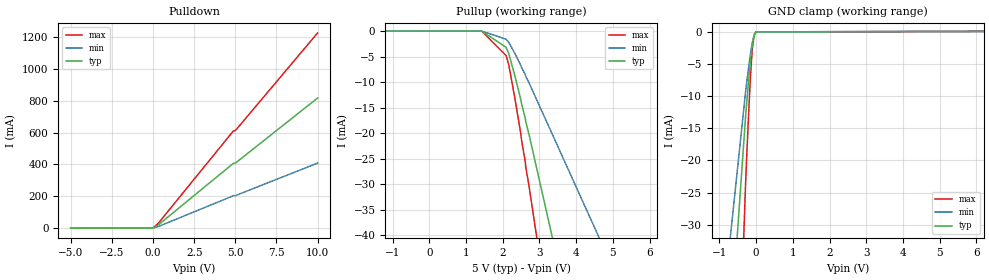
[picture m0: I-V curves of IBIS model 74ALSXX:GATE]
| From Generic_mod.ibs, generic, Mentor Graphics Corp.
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[Model]   74ALSXX:GATE
Model_type   I/O
Polarity   Non-Inverting
Vinl  =   0.800V
Vinh  =   2.000V
Vmeas =   1.500V
Cref  =  50.000pF
Rref  =   1.000kOhm
Vref  =   0.000V
|   typ   min   max
C_comp   5.000pF   2.500pF   7.500pF
[Voltage Range]   5.000V   4.500V   5.500V
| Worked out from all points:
|   slope of the pulldown table from 0 to 0.75 V, typ, clamps not added: 13.1 ohm
|   GND clamp passes 1 mA (typ) near -0.07 V on its own axis
[Pulldown]
| Voltage   I(typ)   I(min)   I(max)
-5V       0A         0A         0A
0V        0A         0A         0A
352mV     23.07mA    11.53mA    34.6mA
4.89V     407.6mA    203.8mA    611.4mA
5V        408.1mA    204.1mA    612.2mA
10V       817.4mA    408.7mA    1.226A
[Pullup]
| Voltage   I(typ)   I(min)   I(max)
-3.571V   0A         0A         0A
1.429V    0A         0A         0A
2.096V    -3.2mA     -1.6mA     -4.8mA
2.17V     -4.5mA     -2.25mA    -6.75mA
2.337V    -8.9mA     -4.45mA    -13.35mA
2.489V    -13.3mA    -6.65mA    -19.95mA
2.519V    -14.4mA    -7.2mA     -21.6mA
2.619V    -17.2mA    -8.6mA     -25.8mA
2.629V    -17.8mA    -8.9mA     -26.7mA
2.709V    -20mA      -10mA      -30mA
6.389V    -137.1mA   -68.55mA   -205.6mA
11.39V    -275mA     -137.5mA   -412.5mA
[GND Clamp]
| Voltage   I(typ)   I(min)   I(max)
-5V       -398mA     -266mA     -792.9mA
-287.6mV  -13.2mA    -9.331mA   -23.71mA
-255.6mV  -10.96mA   -7.82mA    -19.31mA
-189.7mV  -6.623mA   -4.878mA   -10.95mA
-157.7mV  -4.718mA   -3.565mA   -7.397mA
-126.8mV  -3.095mA   -2.424mA   -4.507mA
-106.8mV  -2.189mA   -1.769mA   -2.995mA
-95.35mV  -1.737mA   -1.433mA   -2.284mA
-66.38mV  -840.9uA   -736.6uA   -995.6uA
-39.12mV  -326uA     -301.8uA   -356uA
0V        0A         0A         0A
10V       128uA      128uA      128uA
[Ramp]
|   typ   min   max
dV/dt_r   1.075V/3.180ns   0.643V/5.724ns   1.445V/2.332ns
dV/dt_f   2.388V/2.400ns   1.801V/4.320ns   2.810V/1.760ns
R_load =  50.000Ohm
|------------------- End of 74ALSXX:GATE --------------------------------------
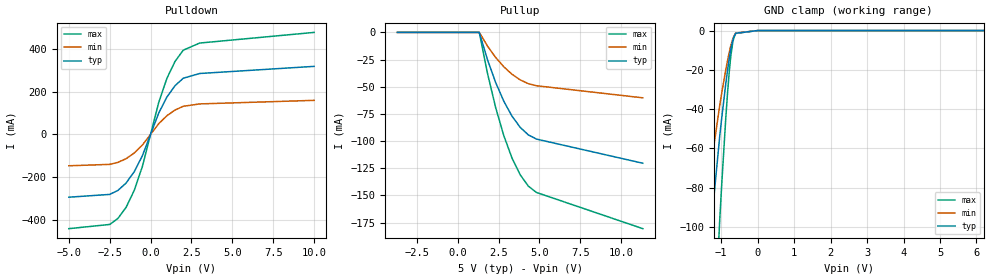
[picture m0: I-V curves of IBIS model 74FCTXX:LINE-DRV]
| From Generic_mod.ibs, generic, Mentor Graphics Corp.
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[Model]   74FCTXX:LINE-DRV
Model_type   I/O
Polarity   Non-Inverting
Vinl  =   0.800V
Vinh  =   2.000V
Vmeas =   1.500V
Cref  =  50.000pF
Rref  =   1.000kOhm
Vref  =   0.000V
|   typ   min   max
C_comp   12.000pF   6.000pF   18.000pF
[Voltage Range]   5.000V   4.500V   5.500V
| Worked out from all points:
|   slope of the pulldown table from 0 to 0.75 V, typ, clamps not added: 5.46 ohm
[Pulldown]
| Voltage   I(typ)   I(min)   I(max)
-5V       -294.3mA   -147.2mA   -441.5mA
-2.5V     -281.2mA   -140.6mA   -421.8mA
-2V       -262.7mA   -131.3mA   -394mA
-1.5V     -228.2mA   -114.1mA   -342.2mA
-1V       -174.9mA   -87.45mA   -262.4mA
-500mV    -100mA     -50mA      -150mA
500mV     100mA      50mA       150mA
1V        174.9mA    87.45mA    262.4mA
1.5V      228.2mA    114.1mA    342.2mA
2V        262.7mA    131.3mA    394mA
3V        284.8mA    142.4mA    427.3mA
10V       318.2mA    159.1mA    477.2mA
[Pullup]
| Voltage   I(typ)   I(min)   I(max)
-3.676V   0A         0A         0A
1.324V    0A         0A         0A
1.824V    -25mA      -12.5mA    -37.5mA
2.324V    -46.05mA   -23.03mA   -69.08mA
2.824V    -63.35mA   -31.67mA   -95.02mA
3.324V    -77.06mA   -38.53mA   -115.6mA
3.824V    -87.34mA   -43.67mA   -131mA
4.324V    -94.33mA   -47.17mA   -141.5mA
4.824V    -98.19mA   -49.09mA   -147.3mA
11.32V    -120.4mA   -60.21mA   -180.6mA
[GND Clamp]
| Voltage   I(typ)   I(min)   I(max)
-5V       -820mA     -549.2mA   -1.627A
-1.036V   -53.26mA   -37.7mA    -95.41mA
-984.1mV  -44.54mA   -31.82mA   -78.32mA
-874.8mV  -27.32mA   -20.14mA   -45.09mA
-822.5mV  -19.88mA   -15.03mA   -31.19mA
-775.2mV  -13.87mA   -10.82mA   -20.4mA
-735.6mV  -9.524mA   -7.699mA   -13.05mA
-678.8mV  -4.762mA   -4.11mA    -5.792mA
-653.9mV  -3.293mA   -2.932mA   -3.809mA
-601.6mV  -1.347mA   -1.27mA    -1.438mA
0V        0A         0A         0A
10V       0A         0A         0A
[Ramp]
|   typ   min   max
dV/dt_r   1.524V/1.500ns   0.973V/2.700ns   1.946V/1.100ns
dV/dt_f   2.727V/1.500ns   2.210V/2.700ns   3.094V/1.100ns
R_load =  50.000Ohm
|------------------- End of 74FCTXX:LINE-DRV ----------------------------------
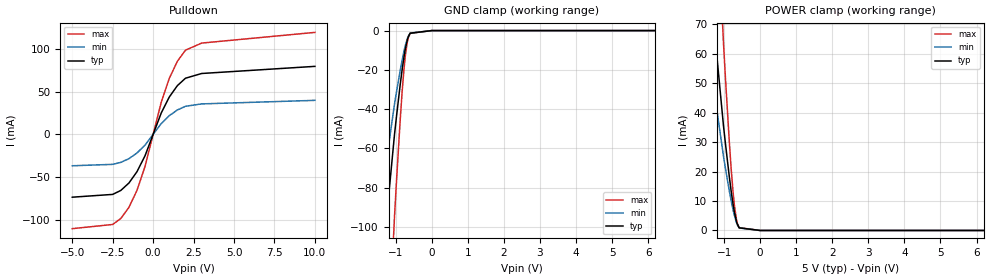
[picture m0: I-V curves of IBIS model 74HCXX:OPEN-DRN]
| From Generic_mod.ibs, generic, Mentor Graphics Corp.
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[Model]   74HCXX:OPEN-DRN
Model_type   I/O_open_drain
Polarity   Non-Inverting
Vinl  =   3.000V
Vinh  =   4.000V
Vmeas =   3.500V
Cref  =  50.000pF
Rref  =   50.00Ohm
Vref  =   5.000V
|   typ   min   max
C_comp   5.000pF   2.500pF   7.500pF
[Voltage Range]   5.000V   4.500V   5.500V
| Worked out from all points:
|   slope of the pulldown table from 0 to 0.75 V, typ, clamps not added: 21.8 ohm
|   POWER clamp passes 1 mA (typ) near -0.59 V on its own axis
[Pulldown]
| Voltage   I(typ)   I(min)   I(max)
-5V       -73.58mA   -36.79mA   -110.4mA
-2.5V     -70.3mA    -35.15mA   -105.5mA
-2V       -65.67mA   -32.83mA   -98.5mA
-1.5V     -57.04mA   -28.52mA   -85.56mA
-1V       -43.73mA   -21.86mA   -65.59mA
-500mV    -25mA      -12.5mA    -37.5mA
500mV     25mA       12.5mA     37.5mA
1V        43.73mA    21.86mA    65.59mA
1.5V      57.04mA    28.52mA    85.56mA
2V        65.67mA    32.83mA    98.5mA
3V        71.21mA    35.61mA    106.8mA
10V       79.54mA    39.77mA    119.3mA
|[Pullup]
| Voltage   I(typ)   I(min)   I(max)
|   0.0000V   0.0000A   0.0000A   0.0000A
|  500.0000mV   0.0000A   0.0000A   0.0000A
| 1000.0000mV   0.0000A   0.0000A   0.0000A
|   1.5000V   0.0000A   0.0000A   0.0000A
|   2.0000V   0.0000A   0.0000A   0.0000A
|   2.5000V   0.0000A   0.0000A   0.0000A
|   3.0000V   0.0000A   0.0000A   0.0000A
|   3.5000V   0.0000A   0.0000A   0.0000A
|   4.0000V   0.0000A   0.0000A   0.0000A
|   4.5000V   0.0000A   0.0000A   0.0000A
|   5.0000V   0.0000A   0.0000A   0.0000A
|   5.5000V   -500.5005nA   -250.2503nA   -750.7508nA
|   6.0000V   -922.0229nA   -461.0115nA   -1.3830uA
|   6.5000V   -1.2682uA   -634.1204nA   -1.9024uA
|   7.0000V   -1.5428uA   -771.4136nA   -2.3142uA
|   7.5000V   -1.7485uA   -874.2687nA   -2.6228uA
|   8.0000V   -1.8886uA   -944.2929nA   -2.8329uA
|   8.5000V   -1.9657uA   -982.8636nA   -2.9486uA
|   9.0000V   -2.0011uA   -1.0005uA   -3.0016uA
|   9.5000V   -2.0351uA   -1.0175uA   -3.0526uA
|   10.0000V   -2.0690uA   -1.0345uA   -3.1036uA
|   15.0000V   -2.4107uA   -1.2053uA   -3.6160uA
[GND Clamp]
| Voltage   I(typ)   I(min)   I(max)
-5V       -820mA     -549.2mA   -1.627A
-1.036V   -53.26mA   -37.7mA    -95.41mA
-984.1mV  -44.54mA   -31.82mA   -78.32mA
-874.8mV  -27.32mA   -20.14mA   -45.09mA
-822.5mV  -19.88mA   -15.03mA   -31.19mA
-775.2mV  -13.87mA   -10.82mA   -20.4mA
-735.6mV  -9.524mA   -7.699mA   -13.05mA
-678.8mV  -4.762mA   -4.11mA    -5.792mA
-653.9mV  -3.293mA   -2.932mA   -3.809mA
-601.6mV  -1.347mA   -1.27mA    -1.438mA
0V        0A         0A         0A
10V       0A         0A         0A
[POWER Clamp]
| Voltage   I(typ)   I(min)   I(max)
-5V       549.2mA    367.8mA    1.09A
-1.017V   35.51mA    25.14mA    63.62mA
-964.9mV  29.7mA     21.22mA    52.23mA
-855.5mV  18.21mA    13.43mA    30.06mA
-803.2mV  13.26mA    10.02mA    20.8mA
-755.9mV  9.247mA    7.215mA    13.6mA
-716.3mV  6.349mA    5.133mA    8.699mA
-659.5mV  3.175mA    2.74mA     3.862mA
-634.6mV  2.195mA    1.955mA    2.54mA
-582.3mV  897.7uA    846.6uA    958.8uA
0V        0A         0A         0A
10V       0A         0A         0A
[Ramp]
|   typ   min   max
dV/dt_r   1.891V/1.800ns   1.061V/3.240ns   2.456V/1.320ns
dV/dt_f   1.891V/1.800ns   1.061V/3.240ns   2.456V/1.320ns
R_load =  50.000Ohm
|------------------- End of 74HCXX:OPEN-DRN -----------------------------------
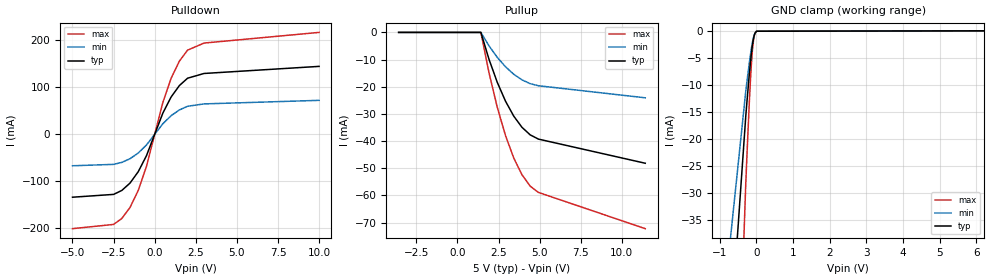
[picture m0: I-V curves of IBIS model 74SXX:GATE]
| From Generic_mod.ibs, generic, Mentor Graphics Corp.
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[Model]   74SXX:GATE
Model_type   I/O
Polarity   Non-Inverting
Vinl  =   0.800V
Vinh  =   2.000V
Vmeas =   1.500V
Cref  =  50.000pF
Rref  =   1.000kOhm
Vref  =   0.000V
|   typ   min   max
C_comp   8.000pF   4.000pF   12.000pF
[Voltage Range]   5.000V   4.500V   5.500V
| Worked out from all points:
|   slope of the pulldown table from 0 to 0.75 V, typ, clamps not added: 12 ohm
|   GND clamp passes 1 mA (typ) near -0.07 V on its own axis
[Pulldown]
| Voltage   I(typ)   I(min)   I(max)
-5V       -133.8mA   -66.89mA   -200.7mA
-2.5V     -127.8mA   -63.91mA   -191.7mA
-2V       -119.4mA   -59.7mA    -179.1mA
-1.5V     -103.7mA   -51.85mA   -155.6mA
-1V       -79.5mA    -39.75mA   -119.3mA
-500mV    -45.45mA   -22.73mA   -68.18mA
500mV     45.45mA    22.73mA    68.18mA
1V        79.5mA     39.75mA    119.3mA
1.5V      103.7mA    51.85mA    155.6mA
2V        119.4mA    59.7mA     179.1mA
3V        129.5mA    64.74mA    194.2mA
10V       144.6mA    72.31mA    216.9mA
[Pullup]
| Voltage   I(typ)   I(min)   I(max)
-3.577V   0A         0A         0A
1.423V    0A         0A         0A
1.923V    -10mA      -5mA       -15mA
2.423V    -18.42mA   -9.211mA   -27.63mA
2.923V    -25.34mA   -12.67mA   -38.01mA
3.423V    -30.83mA   -15.41mA   -46.24mA
3.923V    -34.94mA   -17.47mA   -52.4mA
4.423V    -37.73mA   -18.87mA   -56.6mA
4.923V    -39.28mA   -19.64mA   -58.91mA
11.42V    -48.17mA   -24.08mA   -72.25mA
[GND Clamp]
| Voltage   I(typ)   I(min)   I(max)
-5V       -477.1mA   -318.8mA   -950.4mA
-292.8mV  -15.86mA   -11.21mA   -28.48mA
-261mV    -13.19mA   -9.409mA   -23.24mA
-194.9mV  -7.964mA   -5.866mA   -13.17mA
-163.1mV  -5.696mA   -4.304mA   -8.933mA
-132mV    -3.732mA   -2.924mA   -5.434mA
-112.1mV  -2.653mA   -2.144mA   -3.63mA
-100.2mV  -2.09mA    -1.726mA   -2.744mA
-71.08mV  -1.017mA   -891.7uA   -1.201mA
-42.9mV   -392uA     -364uA     -426.5uA
0V        0A         0A         0A
10V       128uA      128uA      128uA
[Ramp]
|   typ   min   max
dV/dt_r   0.930V/1.500ns   0.493V/2.700ns   1.323V/1.100ns
dV/dt_f   2.392V/900.000ps   1.660V/1.620ns   2.840V/660.000ps
R_load =  50.000Ohm
|------------------- End of 74SXX:GATE ----------------------------------------
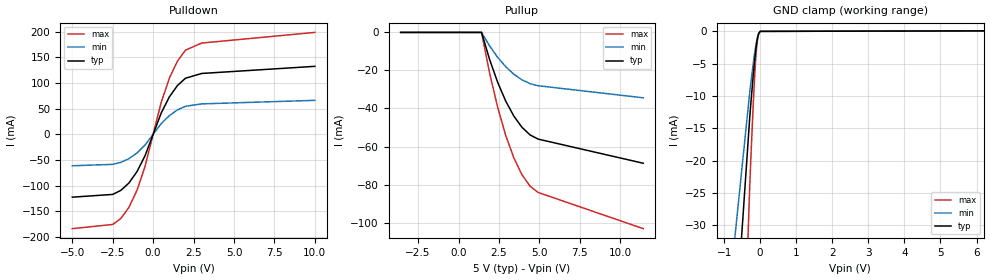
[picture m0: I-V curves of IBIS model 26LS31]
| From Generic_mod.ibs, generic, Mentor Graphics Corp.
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[Model]   26LS31
Model_type   I/O
Polarity   Non-Inverting
Vinl  =   0.800V
Vinh  =   2.000V
Vmeas =   1.500V
Cref  =  50.000pF
Rref  =   1.000kOhm
Vref  =   0.000V
|   typ   min   max
C_comp   5.000pF   2.500pF   7.500pF
[Voltage Range]   5.000V   4.500V   5.500V
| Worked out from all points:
|   slope of the pulldown table from 0 to 0.75 V, typ, clamps not added: 13.1 ohm
|   GND clamp passes 1 mA (typ) near -0.07 V on its own axis
[Pulldown]
| Voltage   I(typ)   I(min)   I(max)
-5V       -122.6mA   -61.32mA   -184mA
-2.5V     -117.2mA   -58.59mA   -175.8mA
-2V       -109.4mA   -54.72mA   -164.2mA
-1.5V     -95.06mA   -47.53mA   -142.6mA
-1V       -72.88mA   -36.44mA   -109.3mA
-500mV    -41.67mA   -20.83mA   -62.5mA
500mV     41.67mA    20.83mA    62.5mA
1V        72.88mA    36.44mA    109.3mA
1.5V      95.06mA    47.53mA    142.6mA
2V        109.4mA    54.72mA    164.2mA
3V        118.7mA    59.34mA    178mA
10V       132.6mA    66.28mA    198.8mA
[Pullup]
| Voltage   I(typ)   I(min)   I(max)
-3.577V   0A         0A         0A
1.423V    0A         0A         0A
1.923V    -14.29mA   -7.143mA   -21.43mA
2.423V    -26.32mA   -13.16mA   -39.48mA
2.923V    -36.2mA    -18.1mA    -54.3mA
3.423V    -44.04mA   -22.02mA   -66.06mA
3.923V    -49.91mA   -24.95mA   -74.86mA
4.423V    -53.91mA   -26.95mA   -80.86mA
4.923V    -56.11mA   -28.05mA   -84.16mA
11.42V    -68.81mA   -34.4mA    -103.2mA
[GND Clamp]
| Voltage   I(typ)   I(min)   I(max)
-5V       -398mA     -266mA     -792.9mA
-287.6mV  -13.2mA    -9.331mA   -23.71mA
-255.6mV  -10.96mA   -7.82mA    -19.31mA
-189.7mV  -6.623mA   -4.878mA   -10.95mA
-157.7mV  -4.718mA   -3.565mA   -7.397mA
-126.8mV  -3.095mA   -2.424mA   -4.507mA
-106.8mV  -2.189mA   -1.769mA   -2.995mA
-95.35mV  -1.737mA   -1.433mA   -2.284mA
-66.38mV  -840.9uA   -736.6uA   -995.6uA
-39.12mV  -326uA     -301.8uA   -356uA
0V        0A         0A         0A
10V       128uA      128uA      128uA
[Ramp]
|   typ   min   max
dV/dt_r   1.156V/3.180ns   0.656V/5.724ns   1.579V/2.332ns
dV/dt_f   2.330V/2.400ns   1.580V/4.320ns   2.798V/1.760ns
R_load =  50.000Ohm
|------------------- End of 26LS31 --------------------------------------------
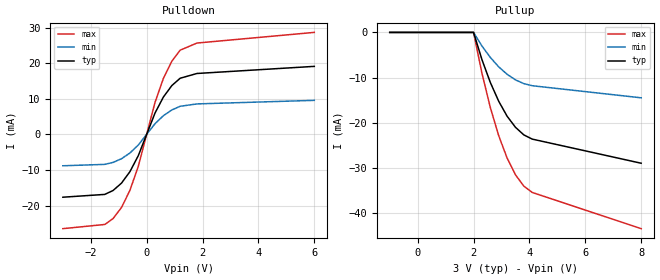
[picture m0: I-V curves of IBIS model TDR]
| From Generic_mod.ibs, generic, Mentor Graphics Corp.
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[Model]   TDR
Model_type   I/O
Polarity   Non-Inverting
Vinl  =   0.100V
Vinh  =   0.900V
Vmeas =   0.500V
Cref  =  50.000pF
Rref  =   1.000kOhm
Vref  =   0.000V
|   typ   min   max
C_comp   0.000F   0.000F   0.000F
[Voltage Range]   3.000V   2.700V   3.300V
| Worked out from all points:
|   slope of the pulldown table from 0 to 0.45 V, typ, clamps not added: 54.6 ohm
[Pulldown]
| Voltage   I(typ)   I(min)   I(max)
-3V       -17.66mA   -8.83mA    -26.49mA
-1.5V     -16.87mA   -8.436mA   -25.31mA
-1.2V     -15.76mA   -7.88mA    -23.64mA
-900mV    -13.69mA   -6.845mA   -20.53mA
-600mV    -10.49mA   -5.247mA   -15.74mA
-300mV    -6mA       -3mA       -9mA
300mV     6mA        3mA        9mA
600mV     10.49mA    5.247mA    15.74mA
900mV     13.69mA    6.845mA    20.53mA
1.2V      15.76mA    7.88mA     23.64mA
1.8V      17.09mA    8.545mA    25.64mA
6V        19.09mA    9.545mA    28.63mA
[Pullup]
| Voltage   I(typ)   I(min)   I(max)
-1V       0A         0A         0A
2V        0A         0A         0A
2.3V      -6mA       -3mA       -9mA
2.6V      -11.05mA   -5.527mA   -16.58mA
2.9V      -15.2mA    -7.602mA   -22.81mA
3.2V      -18.5mA    -9.248mA   -27.74mA
3.5V      -20.96mA   -10.48mA   -31.44mA
3.8V      -22.64mA   -11.32mA   -33.96mA
4.1V      -23.57mA   -11.78mA   -35.35mA
8V        -28.9mA    -14.45mA   -43.35mA
[Ramp]
|   typ   min   max
dV/dt_r   0.290V/60.000ps   0.134V/108.000ps   0.454V/44.000ps
dV/dt_f   0.517V/60.000ps   0.260V/108.000ps   0.774V/44.000ps
R_load =  50.000Ohm
|------------------- End of TDR -----------------------------------------------
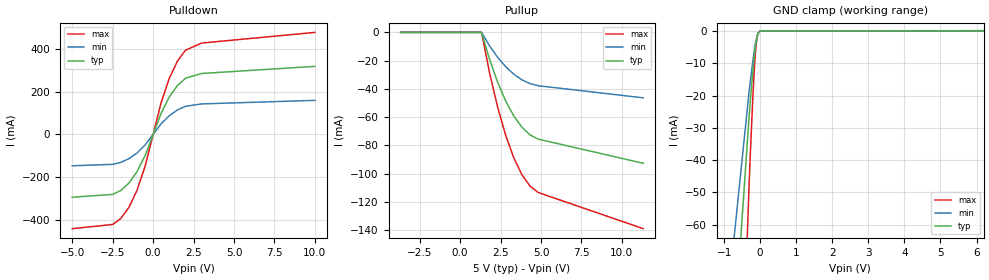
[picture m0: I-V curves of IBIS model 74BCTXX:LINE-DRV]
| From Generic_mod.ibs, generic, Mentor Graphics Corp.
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[Model]   74BCTXX:LINE-DRV
Model_type   I/O
Polarity   Non-Inverting
Vinl  =   0.800V
Vinh  =   2.000V
Vmeas =   1.500V
Cref  =  50.000pF
Rref  =   1.000kOhm
Vref  =   0.000V
|   typ   min   max
C_comp   9.000pF   4.500pF   13.500pF
[Voltage Range]   5.000V   4.500V   5.500V
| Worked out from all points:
|   slope of the pulldown table from 0 to 0.75 V, typ, clamps not added: 5.46 ohm
|   GND clamp passes 1 mA (typ) near -0.07 V on its own axis
[Pulldown]
| Voltage   I(typ)   I(min)   I(max)
-5V       -294.3mA   -147.2mA   -441.5mA
-2.5V     -281.2mA   -140.6mA   -421.8mA
-2V       -262.7mA   -131.3mA   -394mA
-1.5V     -228.2mA   -114.1mA   -342.2mA
-1V       -174.9mA   -87.45mA   -262.4mA
-500mV    -100mA     -50mA      -150mA
500mV     100mA      50mA       150mA
1V        174.9mA    87.45mA    262.4mA
1.5V      228.2mA    114.1mA    342.2mA
2V        262.7mA    131.3mA    394mA
3V        284.8mA    142.4mA    427.3mA
10V       318.2mA    159.1mA    477.2mA
[Pullup]
| Voltage   I(typ)   I(min)   I(max)
-3.676V   0A         0A         0A
1.324V    0A         0A         0A
1.824V    -19.23mA   -9.615mA   -28.85mA
2.324V    -35.43mA   -17.71mA   -53.14mA
2.824V    -48.73mA   -24.36mA   -73.09mA
3.324V    -59.28mA   -29.64mA   -88.92mA
3.824V    -67.18mA   -33.59mA   -100.8mA
4.324V    -72.57mA   -36.28mA   -108.8mA
4.824V    -75.53mA   -37.76mA   -113.3mA
11.32V    -92.63mA   -46.31mA   -138.9mA
[GND Clamp]
| Voltage   I(typ)   I(min)   I(max)
-5V       -792.9mA   -529.8mA   -1.579A
-307.3mV  -26.48mA   -18.72mA   -47.54mA
-276mV    -22.09mA   -15.77mA   -38.96mA
-209.4mV  -13.33mA   -9.818mA   -22.03mA
-169.9mV  -8.696mA   -6.624mA   -13.42mA
-138.6mV  -5.533mA   -4.388mA   -7.867mA
-114.2mV  -3.513mA   -2.906mA   -4.602mA
-95.35mV  -2.284mA   -1.963mA   -2.793mA
-81.65mV  -1.585mA   -1.404mA   -1.848mA
-54.29mV  -655uA     -611.8uA   -707.5uA
0V        0A         0A         0A
10V       128uA      128uA      128uA
[Ramp]
|   typ   min   max
dV/dt_r   1.372V/1.500ns   0.825V/2.700ns   1.801V/1.100ns
dV/dt_f   2.723V/1.500ns   2.207V/2.700ns   3.090V/1.100ns
R_load =  50.000Ohm
|------------------- End of 74BCTXX:LINE-DRV ----------------------------------
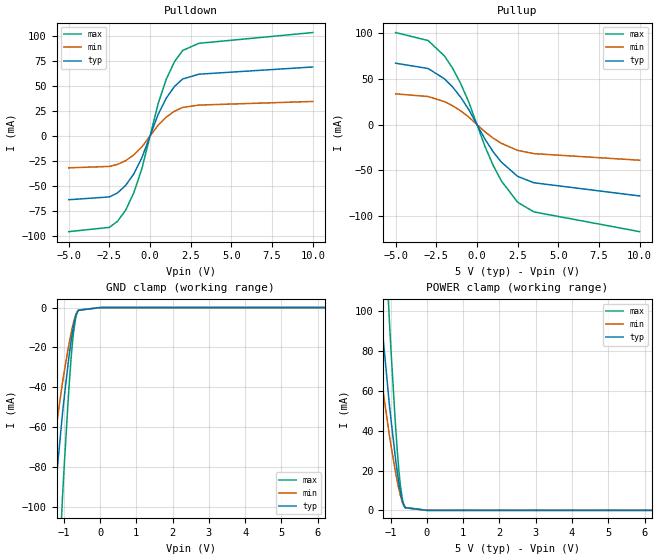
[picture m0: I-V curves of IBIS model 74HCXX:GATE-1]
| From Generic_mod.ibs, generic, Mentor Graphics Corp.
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[Model]   74HCXX:GATE-1
Model_type   I/O
Polarity   Non-Inverting
Vinl  =   0.800V
Vinh  =   2.000V
Vmeas =   1.500V
Cref  =   0.000F
Rref  =   1.000MOhm
Vref  =   0.000V
|   typ   min   max
C_comp   5.000pF   2.500pF   7.500pF
[Voltage Range]   5.000V   4.500V   5.500V
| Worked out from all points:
|   slope of the pulldown table from 0 to 0.75 V, typ, clamps not added: 25.1 ohm
|   slope of the pullup table from 0 to 0.75 V, typ, clamps not added: 32.7 ohm
[Pulldown]
| Voltage   I(typ)   I(min)   I(max)
-5V       -63.99mA   -31.99mA   -95.98mA
-2.5V     -61.13mA   -30.57mA   -91.7mA
-2V       -57.1mA    -28.55mA   -85.65mA
-1.5V     -49.6mA    -24.8mA    -74.4mA
-1V       -38.02mA   -19.01mA   -57.03mA
-500mV    -21.74mA   -10.87mA   -32.61mA
500mV     21.74mA    10.87mA    32.61mA
1V        38.02mA    19.01mA    57.03mA
1.5V      49.6mA     24.8mA     74.4mA
2V        57.1mA     28.55mA    85.65mA
3V        61.92mA    30.96mA    92.88mA
10V       69.16mA    34.58mA    103.7mA
[Pullup]
| Voltage   I(typ)   I(min)   I(max)
-5V       66.68mA    33.34mA    100mA
-3V       60.86mA    30.43mA    91.29mA
-2V       49.72mA    24.86mA    74.58mA
-1.5V     40.87mA    20.43mA    61.31mA
-1V       29.71mA    14.86mA    44.57mA
-500mV    16.13mA    8.065mA    24.19mA
500mV     -16.13mA   -8.065mA   -24.19mA
1V        -29.71mA   -14.86mA   -44.57mA
1.5V      -40.87mA   -20.43mA   -61.31mA
2.5V      -56.35mA   -28.17mA   -84.52mA
3.5V      -63.35mA   -31.67mA   -95.02mA
10V       -77.69mA   -38.84mA   -116.5mA
[GND Clamp]
| Voltage   I(typ)   I(min)   I(max)
-5V       -820mA     -549.2mA   -1.627A
-1.036V   -53.26mA   -37.7mA    -95.41mA
-984.1mV  -44.54mA   -31.82mA   -78.32mA
-874.8mV  -27.32mA   -20.14mA   -45.09mA
-822.5mV  -19.88mA   -15.03mA   -31.19mA
-775.2mV  -13.87mA   -10.82mA   -20.4mA
-735.6mV  -9.524mA   -7.699mA   -13.05mA
-678.8mV  -4.762mA   -4.11mA    -5.792mA
-653.9mV  -3.293mA   -2.932mA   -3.809mA
-601.6mV  -1.347mA   -1.27mA    -1.438mA
0V        0A         0A         0A
10V       0A         0A         0A
[POWER Clamp]
| Voltage   I(typ)   I(min)   I(max)
-5V       820mA      549.2mA    1.627A
-1.036V   53.26mA    37.7mA     95.41mA
-984.1mV  44.54mA    31.82mA    78.32mA
-874.8mV  27.32mA    20.14mA    45.09mA
-822.5mV  19.88mA    15.03mA    31.19mA
-775.2mV  13.87mA    10.82mA    20.4mA
-735.6mV  9.524mA    7.699mA    13.05mA
-678.8mV  4.762mA    4.11mA     5.792mA
-653.9mV  3.293mA    2.932mA    3.809mA
-601.6mV  1.347mA    1.27mA     1.438mA
0V        0A         0A         0A
10V       0A         0A         0A
[Ramp]
|   typ   min   max
dV/dt_r   1.615V/3.600ns   0.911V/6.480ns   2.159V/2.640ns
dV/dt_f   1.738V/3.600ns   0.928V/6.480ns   2.321V/2.640ns
R_load =  50.000Ohm
|------------------- End of 74HCXX:GATE-1 -------------------------------------
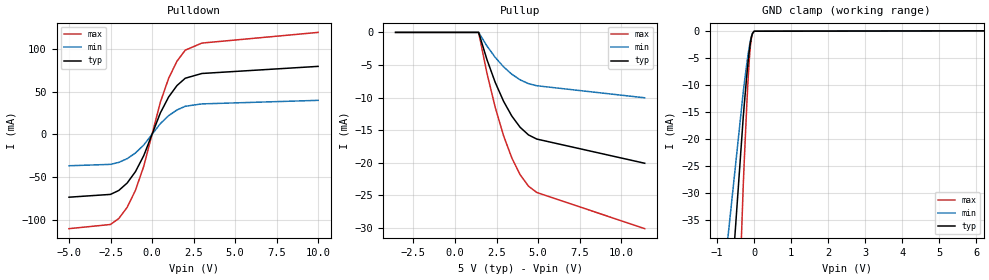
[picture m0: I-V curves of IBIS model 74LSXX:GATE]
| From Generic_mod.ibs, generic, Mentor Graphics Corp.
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[Model]   74LSXX:GATE
Model_type   I/O
Polarity   Non-Inverting
Vinl  =   0.800V
Vinh  =   2.000V
Vmeas =   1.500V
Cref  =   0.000F
Rref  =   1.000MOhm
Vref  =   0.000V
|   typ   min   max
C_comp   5.000pF   2.500pF   7.500pF
[Voltage Range]   5.000V   4.500V   5.500V
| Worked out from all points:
|   slope of the pulldown table from 0 to 0.75 V, typ, clamps not added: 21.8 ohm
|   GND clamp passes 1 mA (typ) near -0.07 V on its own axis
[Pulldown]
| Voltage   I(typ)   I(min)   I(max)
-5V       -73.58mA   -36.79mA   -110.4mA
-2.5V     -70.3mA    -35.15mA   -105.5mA
-2V       -65.67mA   -32.83mA   -98.5mA
-1.5V     -57.04mA   -28.52mA   -85.56mA
-1V       -43.73mA   -21.86mA   -65.59mA
-500mV    -25mA      -12.5mA    -37.5mA
500mV     25mA       12.5mA     37.5mA
1V        43.73mA    21.86mA    65.59mA
1.5V      57.04mA    28.52mA    85.56mA
2V        65.67mA    32.83mA    98.5mA
3V        71.21mA    35.61mA    106.8mA
10V       79.54mA    39.77mA    119.3mA
[Pullup]
| Voltage   I(typ)   I(min)   I(max)
-3.577V   0A         0A         0A
1.423V    0A         0A         0A
1.923V    -4.167mA   -2.083mA   -6.25mA
2.423V    -7.676mA   -3.838mA   -11.51mA
2.923V    -10.56mA   -5.279mA   -15.84mA
3.423V    -12.84mA   -6.422mA   -19.27mA
3.923V    -14.56mA   -7.278mA   -21.83mA
4.423V    -15.72mA   -7.861mA   -23.58mA
4.923V    -16.36mA   -8.182mA   -24.55mA
11.42V    -20.07mA   -10.03mA   -30.1mA
[GND Clamp]
| Voltage   I(typ)   I(min)   I(max)
-5V       -477.1mA   -318.8mA   -950.4mA
-292.8mV  -15.86mA   -11.21mA   -28.48mA
-261mV    -13.19mA   -9.409mA   -23.24mA
-194.9mV  -7.964mA   -5.866mA   -13.17mA
-163.1mV  -5.696mA   -4.304mA   -8.933mA
-132mV    -3.732mA   -2.924mA   -5.434mA
-112.1mV  -2.653mA   -2.144mA   -3.63mA
-100.2mV  -2.09mA    -1.726mA   -2.744mA
-71.08mV  -1.017mA   -891.7uA   -1.201mA
-42.9mV   -392uA     -364uA     -426.5uA
0V        0A         0A         0A
10V       128uA      128uA      128uA
[Ramp]
|   typ   min   max
dV/dt_r   0.458V/4.860ns   0.225V/8.748ns   0.698V/3.564ns
dV/dt_f   1.888V/1.920ns   1.059V/3.456ns   2.361V/1.408ns
R_load =  50.000Ohm
|------------------- End of 74LSXX:GATE ---------------------------------------
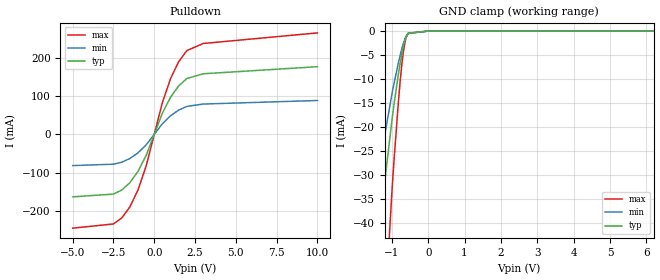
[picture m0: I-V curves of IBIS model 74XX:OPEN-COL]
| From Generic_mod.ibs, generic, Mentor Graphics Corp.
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[Model]   74XX:OPEN-COL
Model_type   I/O_open_drain
Polarity   Non-Inverting
Vinl  =   0.800V
Vinh  =   2.000V
Vmeas =   1.800V
Cref  =   0.000F
Rref  =   50.0Ohm
Vref  =   5.000V
|   typ   min   max
C_comp   5.000pF   2.500pF   7.500pF
[Voltage Range]   5.000V   4.500V   5.500V
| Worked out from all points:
|   slope of the pulldown table from 0 to 0.75 V, typ, clamps not added: 9.82 ohm
|   GND clamp passes 1 mA (typ) near -0.59 V on its own axis
[Pulldown]
| Voltage   I(typ)   I(min)   I(max)
-5V       -163.5mA   -81.76mA   -245.3mA
-2.5V     -156.2mA   -78.11mA   -234.3mA
-2V       -145.9mA   -72.97mA   -218.9mA
-1.5V     -126.8mA   -63.38mA   -190.1mA
-1V       -97.17mA   -48.58mA   -145.8mA
-500mV    -55.56mA   -27.78mA   -83.33mA
500mV     55.56mA    27.78mA    83.33mA
1V        97.17mA    48.58mA    145.8mA
1.5V      126.8mA    63.38mA    190.1mA
2V        145.9mA    72.97mA    218.9mA
3V        158.2mA    79.12mA    237.4mA
10V       176.8mA    88.38mA    265.1mA
|[Pullup]
| Voltage   I(typ)   I(min)   I(max)
|   -4.0000V   0.0000A   0.0000A   0.0000A
|   -3.5000V   0.0000A   0.0000A   0.0000A
|   -3.0000V   0.0000A   0.0000A   0.0000A
|   -2.5000V   0.0000A   0.0000A   0.0000A
|   -2.0000V   0.0000A   0.0000A   0.0000A
|   -1.5000V   0.0000A   0.0000A   0.0000A
|-1000.0000mV   0.0000A   0.0000A   0.0000A
| -500.0000mV   0.0000A   0.0000A   0.0000A
|   0.0000V   0.0000A   0.0000A   0.0000A
|  500.0000mV   0.0000A   0.0000A   0.0000A
| 1000.0000mV   0.0000A   0.0000A   0.0000A
|   1.5000V   -500.0005nA   -250.0003nA   -750.0008nA
|   2.0000V   -921.1018nA   -460.5509nA   -1.3817uA
|   2.5000V   -1.2670uA   -633.4869nA   -1.9005uA
|   3.0000V   -1.5413uA   -770.6429nA   -2.3119uA
|   3.5000V   -1.7468uA   -873.3953nA   -2.6202uA
|   4.0000V   -1.8867uA   -943.3495nA   -2.8300uA
|   4.5000V   -1.9638uA   -981.8817nA   -2.9456uA
|   5.0000V   -1.9991uA   -999.5423nA   -2.9986uA
|   5.5000V   -2.0330uA   -1.0165uA   -3.0495uA
|   6.0000V   -2.0670uA   -1.0335uA   -3.1005uA
|   11.0000V   -2.4083uA   -1.2041uA   -3.6124uA
[GND Clamp]
| Voltage   I(typ)   I(min)   I(max)
-5V       -276.8mA   -185.4mA   -549.2mA
-984.1mV  -17.76mA   -12.57mA   -31.82mA
-932mV    -14.86mA   -10.62mA   -26.13mA
-822.5mV  -9.107mA   -6.716mA   -15.03mA
-770.2mV  -6.63mA    -5.012mA   -10.4mA
-722.9mV  -4.624mA   -3.608mA   -6.799mA
-683.3mV  -3.175mA   -2.567mA   -4.35mA
-626.5mV  -1.587mA   -1.37mA    -1.931mA
-601.6mV  -1.098mA   -977.4uA   -1.27mA
-549.3mV  -448.8uA   -423.3uA   -479.4uA
0V        0A         0A         0A
10V       0A         0A         0A
[Ramp]
|   typ   min   max
dV/dt_r   2.491V/300ps   1.841V/540ps   2.931V/220ps
dV/dt_f   2.491V/3.000ns   1.841V/5.400ns   2.931V/2.200ns
R_load =  50.000Ohm
|------------------- End of 74XX:OPEN-COL -------------------------------------
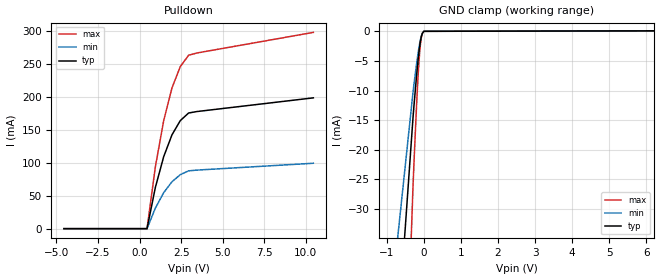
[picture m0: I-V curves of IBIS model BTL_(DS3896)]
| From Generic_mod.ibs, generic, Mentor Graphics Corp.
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[Model]   BTL_(DS3896)
Model_type   I/O_open_drain
Polarity   Non-Inverting
Vinl  =   0.800V
Vinh  =   3.000V
Vmeas =   2.000V
Cref  =   0.000F
Rref  =   50Ohm
Vref  =   5.000V
|   typ   min   max
C_comp   3.000pF   1.500pF   4.500pF
[Voltage Range]   5.000V   4.500V   5.500V
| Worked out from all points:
|   slope of the pulldown table from 0 to 0.75 V, typ, clamps not added: 20 ohm
|   GND clamp passes 1 mA (typ) near -0.07 V on its own axis
[Pulldown]
| Voltage   I(typ)   I(min)   I(max)
-4.55V    0A         0A         0A
450mV     0A         0A         0A
950mV     62.5mA     31.25mA    93.75mA
1.45V     109.3mA    54.66mA    164mA
1.95V     142.6mA    71.3mA     213.9mA
2.45V     164.2mA    82.09mA    246.3mA
2.95V     175.8mA    87.88mA    263.6mA
3.45V     178mA      89.01mA    267mA
10.45V    198.8mA    99.42mA    298.3mA
|[Pullup]
| Voltage   I(typ)   I(min)   I(max)
|   -5.0000V   2.0670uA   1.0335uA   3.1005uA
|   -4.5000V   2.0330uA   1.0165uA   3.0495uA
|   -4.0000V   1.9991uA   999.5423nA   2.9986uA
|   -3.5000V   1.9638uA   981.8817nA   2.9456uA
|   -3.0000V   1.8867uA   943.3495nA   2.8300uA
|   -2.5000V   1.7468uA   873.3953nA   2.6202uA
|   -2.0000V   1.5413uA   770.6429nA   2.3119uA
|   -1.5000V   1.2670uA   633.4869nA   1.9005uA
|-1000.0000mV   921.1018nA   460.5509nA   1.3817uA
| -500.0000mV   500.0005nA   250.0003nA   750.0008nA
|   0.0000V   3.2587fA   1.6294fA   4.8881fA
|  500.0000mV   -500.0005nA   -250.0003nA   -750.0008nA
| 1000.0000mV   -921.1018nA   -460.5509nA   -1.3817uA
|   1.5000V   -1.2670uA   -633.4869nA   -1.9005uA
|   2.0000V   -1.5413uA   -770.6429nA   -2.3119uA
|   2.5000V   -1.7468uA   -873.3953nA   -2.6202uA
|   3.0000V   -1.8867uA   -943.3495nA   -2.8300uA
|   3.5000V   -1.9638uA   -981.8817nA   -2.9456uA
|   4.0000V   -1.9991uA   -999.5423nA   -2.9986uA
|   4.5000V   -2.0330uA   -1.0165uA   -3.0495uA
|   5.0000V   -2.0670uA   -1.0335uA   -3.1005uA
|   10.0000V   -2.4083uA   -1.2041uA   -3.6124uA
[GND Clamp]
| Voltage   I(typ)   I(min)   I(max)
-5V       -434mA     -290mA     -864.5mA
-290.1mV  -14.41mA   -10.18mA   -25.88mA
-258.2mV  -11.97mA   -8.542mA   -21.1mA
-192.2mV  -7.232mA   -5.327mA   -11.96mA
-160.3mV  -5.162mA   -3.901mA   -8.095mA
-129.3mV  -3.385mA   -2.651mA   -4.928mA
-109.4mV  -2.4mA     -1.939mA   -3.284mA
-97.7mV   -1.899mA   -1.567mA   -2.495mA
-68.62mV  -920.8uA   -807.1uA   -1.089mA
-40.9mV   -356uA     -330.1uA   -388.1uA
0V        0A         0A         0A
10V       128uA      128uA      128uA
[Ramp]
|   typ   min   max
dV/dt_r   2.256V/300.000ps   1.756V/540.0ps   2.734V/220.0ps
dV/dt_f   2.329V/2.730ns   1.756V/4.914ns   2.734V/2.002ns
R_load =  50.000Ohm
|------------------- End of BTL_(DS3896) --------------------------------------
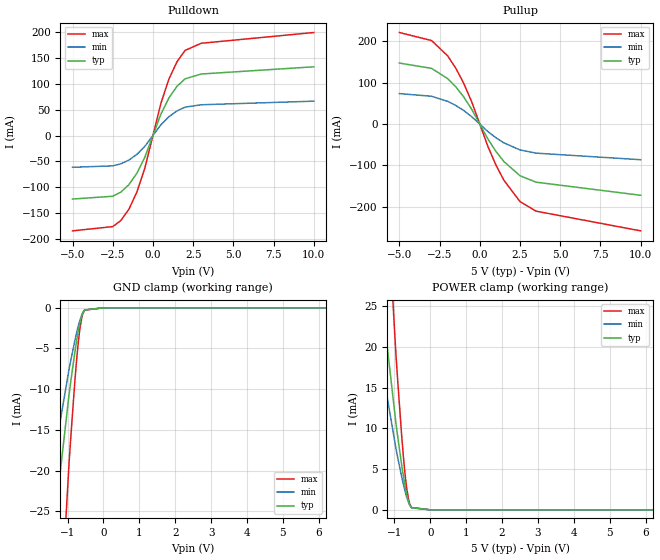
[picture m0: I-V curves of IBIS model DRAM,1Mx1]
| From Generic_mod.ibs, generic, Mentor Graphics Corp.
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[Model]   DRAM,1Mx1
Model_type   I/O
Polarity   Non-Inverting
Vinl  =   0.800V
Vinh  =   2.000V
Vmeas =   1.500V
Cref  =  50.000pF
Rref  =   1.000kOhm
Vref  =   0.000V
|   typ   min   max
C_comp   5.000pF   2.500pF   7.500pF
[Voltage Range]   5.000V   4.500V   5.500V
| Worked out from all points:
|   slope of the pulldown table from 0 to 0.75 V, typ, clamps not added: 13.1 ohm
|   slope of the pullup table from 0 to 0.75 V, typ, clamps not added: 14.8 ohm
|   GND clamp passes 1 mA (typ) near -0.61 V on its own axis
|   POWER clamp passes 1 mA (typ) near -0.61 V on its own axis
[Pulldown]
| Voltage   I(typ)   I(min)   I(max)
-5V       -122.6mA   -61.32mA   -184mA
-2.5V     -117.2mA   -58.59mA   -175.8mA
-2V       -109.4mA   -54.72mA   -164.2mA
-1.5V     -95.06mA   -47.53mA   -142.6mA
-1V       -72.88mA   -36.44mA   -109.3mA
-500mV    -41.67mA   -20.83mA   -62.5mA
500mV     41.67mA    20.83mA    62.5mA
1V        72.88mA    36.44mA    109.3mA
1.5V      95.06mA    47.53mA    142.6mA
2V        109.4mA    54.72mA    164.2mA
3V        118.7mA    59.34mA    178mA
10V       132.6mA    66.28mA    198.8mA
[Pullup]
| Voltage   I(typ)   I(min)   I(max)
-5V       147.6mA    73.82mA    221.5mA
-3V       134.8mA    67.38mA    202.1mA
-2V       110.1mA    55.05mA    165.1mA
-1.5V     90.5mA     45.25mA    135.7mA
-1V       65.79mA    32.9mA     98.69mA
-500mV    35.71mA    17.86mA    53.57mA
500mV     -35.71mA   -17.86mA   -53.57mA
1V        -65.79mA   -32.9mA    -98.69mA
1.5V      -90.5mA    -45.25mA   -135.7mA
2.5V      -124.8mA   -62.39mA   -187.2mA
3.5V      -140.3mA   -70.13mA   -210.4mA
10V       -172mA     -86.01mA   -258mA
[GND Clamp]
| Voltage   I(typ)   I(min)   I(max)
-5V       -167mA     -111.9mA   -331.4mA
-959.9mV  -10.66mA   -7.546mA   -19.1mA
-907.8mV  -8.916mA   -6.371mA   -15.68mA
-798.2mV  -5.465mA   -4.03mA    -9.021mA
-745.9mV  -3.978mA   -3.007mA   -6.241mA
-698.6mV  -2.774mA   -2.165mA   -4.08mA
-659mV    -1.905mA   -1.54mA    -2.61mA
-602.2mV  -952.4uA   -821.9uA   -1.159mA
-577.2mV  -658.6uA   -586.4uA   -761.9uA
-524.9mV  -269.3uA   -254uA     -287.6uA
0V        0A         0A         0A
10V       0A         0A         0A
[POWER Clamp]
| Voltage   I(typ)   I(min)   I(max)
-5V       167mA      111.9mA    331.4mA
-959.9mV  10.66mA    7.546mA    19.1mA
-907.8mV  8.916mA    6.371mA    15.68mA
-798.2mV  5.465mA    4.03mA     9.021mA
-745.9mV  3.978mA    3.007mA    6.241mA
-698.6mV  2.774mA    2.165mA    4.08mA
-659mV    1.905mA    1.54mA     2.61mA
-602.2mV  952.4uA    821.9uA    1.159mA
-577.2mV  658.6uA    586.4uA    761.9uA
-524.9mV  269.3uA    254uA      287.6uA
0V        0A         0A         0A
10V       0A         0A         0A
[Ramp]
|   typ   min   max
dV/dt_r   2.277V/2.700ns   1.576V/4.860ns   2.747V/1.980ns
dV/dt_f   2.334V/2.700ns   1.582V/4.860ns   2.802V/1.980ns
R_load =  50.000Ohm
|------------------- End of DRAM,1Mx1 -----------------------------------------
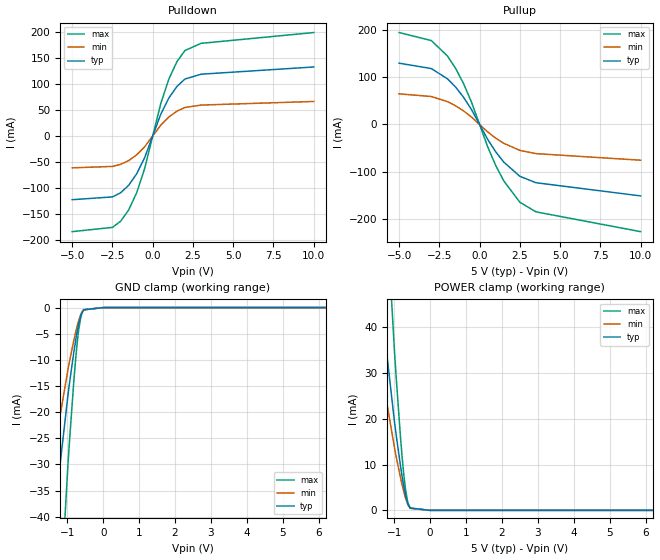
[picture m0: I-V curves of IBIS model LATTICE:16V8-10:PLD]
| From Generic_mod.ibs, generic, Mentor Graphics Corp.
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[Model]   LATTICE:16V8-10:PLD
Model_type   I/O
Polarity   Non-Inverting
Vinl  =   0.800V
Vinh  =   2.000V
Vmeas =   1.500V
Cref  =  50.000pF
Rref  =   1.000kOhm
Vref  =   0.000V
|   typ   min   max
C_comp   10.000pF   5.000pF   15.000pF
[Voltage Range]   5.000V   4.500V   5.500V
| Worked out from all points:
|   slope of the pulldown table from 0 to 0.75 V, typ, clamps not added: 13.1 ohm
|   slope of the pullup table from 0 to 0.75 V, typ, clamps not added: 16.9 ohm
|   GND clamp passes 1 mA (typ) near -0.60 V on its own axis
|   POWER clamp passes 1 mA (typ) near -0.59 V on its own axis
[Pulldown]
| Voltage   I(typ)   I(min)   I(max)
-5V       -122.6mA   -61.32mA   -184mA
-2.5V     -117.2mA   -58.59mA   -175.8mA
-2V       -109.4mA   -54.72mA   -164.2mA
-1.5V     -95.06mA   -47.53mA   -142.6mA
-1V       -72.88mA   -36.44mA   -109.3mA
-500mV    -41.67mA   -20.83mA   -62.5mA
500mV     41.67mA    20.83mA    62.5mA
1V        72.88mA    36.44mA    109.3mA
1.5V      95.06mA    47.53mA    142.6mA
2V        109.4mA    54.72mA    164.2mA
3V        118.7mA    59.34mA    178mA
10V       132.6mA    66.28mA    198.8mA
[Pullup]
| Voltage   I(typ)   I(min)   I(max)
-5V       129.2mA    64.59mA    193.8mA
-3V       117.9mA    58.96mA    176.9mA
-2V       96.33mA    48.17mA    144.5mA
-1.5V     79.19mA    39.59mA    118.8mA
-1V       57.57mA    28.78mA    86.35mA
-500mV    31.25mA    15.62mA    46.88mA
500mV     -31.25mA   -15.62mA   -46.88mA
1V        -57.57mA   -28.78mA   -86.35mA
1.5V      -79.19mA   -39.59mA   -118.8mA
2.5V      -109.2mA   -54.59mA   -163.8mA
3.5V      -122.7mA   -61.37mA   -184.1mA
10V       -150.5mA   -75.26mA   -225.8mA
[GND Clamp]
| Voltage   I(typ)   I(min)   I(max)
-5V       -259.7mA   -173.9mA   -515.2mA
-981.1mV  -16.65mA   -11.79mA   -29.84mA
-928.9mV  -13.93mA   -9.952mA   -24.49mA
-819.4mV  -8.538mA   -6.296mA   -14.09mA
-767.1mV  -6.216mA   -4.699mA   -9.751mA
-719.9mV  -4.335mA   -3.382mA   -6.374mA
-680.2mV  -2.976mA   -2.406mA   -4.078mA
-623.4mV  -1.488mA   -1.284mA   -1.81mA
-598.5mV  -1.029mA   -916.3uA   -1.19mA
-546.2mV  -420.8uA   -396.8uA   -449.4uA
0V        0A         0A         0A
10V       0A         0A         0A
[POWER Clamp]
| Voltage   I(typ)   I(min)   I(max)
-5V       296.3mA    198.4mA    588mA
-987.4mV  19.03mA    13.47mA    34.1mA
-935.3mV  15.92mA    11.37mA    27.99mA
-825.8mV  9.758mA    7.196mA    16.11mA
-773.5mV  7.103mA    5.37mA     11.14mA
-726.2mV  4.954mA    3.865mA    7.285mA
-686.6mV  3.401mA    2.75mA     4.66mA
-629.8mV  1.701mA    1.468mA    2.069mA
-604.9mV  1.176mA    1.047mA    1.361mA
-552.5mV  480.9uA    453.5uA    513.6uA
0V        0A         0A         0A
10V       0A         0A         0A
[Ramp]
|   typ   min   max
dV/dt_r   2.187V/450.000ps   1.466V/810.000ps   2.674V/330.000ps
dV/dt_f   2.334V/450.000ps   1.582V/810.000ps   2.802V/330.000ps
R_load =  50.000Ohm
|------------------- End of LATTICE:16V8-10:PLD -------------------------------
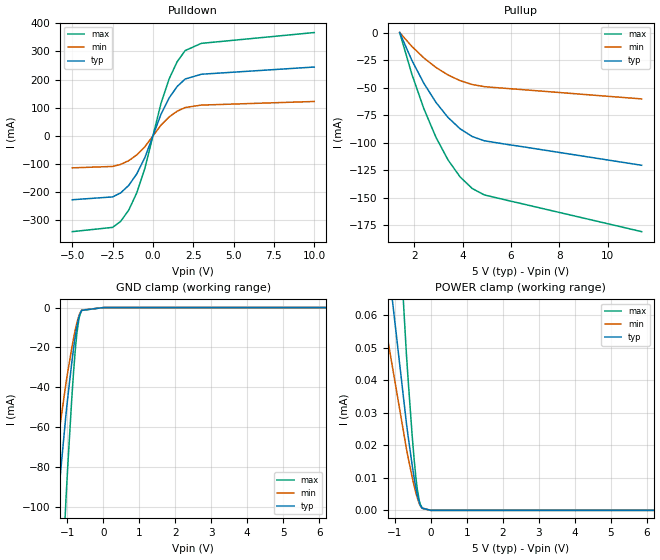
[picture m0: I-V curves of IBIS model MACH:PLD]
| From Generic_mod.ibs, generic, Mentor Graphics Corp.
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[Model]   MACH:PLD
Model_type   I/O
Polarity   Non-Inverting
Vinl  =   0.800V
Vinh  =   2.000V
Vmeas =   1.500V
Cref  =  50.000pF
Rref  =   1.000kOhm
Vref  =   0.000V
|   typ   min   max
C_comp   8.000pF   4.000pF   12.000pF
[Voltage Range]   5.000V   4.500V   5.500V
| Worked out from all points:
|   slope of the pulldown table from 0 to 0.75 V, typ, clamps not added: 7.09 ohm
[Pulldown]
| Voltage   I(typ)   I(min)   I(max)
-5V       -226.4mA   -113.2mA   -339.6mA
-2.5V     -216.3mA   -108.2mA   -324.5mA
-2V       -202.1mA   -101mA     -303.1mA
-1.5V     -175.5mA   -87.75mA   -263.3mA
-1V       -134.5mA   -67.27mA   -201.8mA
-500mV    -76.92mA   -38.46mA   -115.4mA
500mV     76.92mA    38.46mA    115.4mA
1V        134.5mA    67.27mA    201.8mA
1.5V      175.5mA    87.75mA    263.3mA
2V        202.1mA    101mA      303.1mA
3V        219.1mA    109.6mA    328.7mA
10V       244.7mA    122.4mA    367.1mA
[Pullup]
| Voltage   I(typ)   I(min)   I(max)
1.4V      0A         0A         0A
1.9V      -25mA      -12.5mA    -37.5mA
2.4V      -46.05mA   -23.03mA   -69.08mA
2.9V      -63.35mA   -31.67mA   -95.02mA
3.4V      -77.06mA   -38.53mA   -115.6mA
3.9V      -87.34mA   -43.67mA   -131mA
4.4V      -94.33mA   -47.17mA   -141.5mA
4.9V      -98.19mA   -49.09mA   -147.3mA
5.4V      -99.95mA   -49.98mA   -149.9mA
5.9V      -101.7mA   -50.83mA   -152.5mA
6.4V      -103.3mA   -51.67mA   -155mA
11.4V     -120.4mA   -60.21mA   -180.6mA
[GND Clamp]
| Voltage   I(typ)   I(min)   I(max)
-5V       -820mA     -549.2mA   -1.627A
-1.036V   -53.26mA   -37.7mA    -95.41mA
-984.1mV  -44.54mA   -31.82mA   -78.32mA
-874.8mV  -27.32mA   -20.14mA   -45.09mA
-822.5mV  -19.88mA   -15.03mA   -31.19mA
-775.2mV  -13.87mA   -10.82mA   -20.4mA
-735.6mV  -9.524mA   -7.699mA   -13.05mA
-678.8mV  -4.762mA   -4.11mA    -5.792mA
-653.9mV  -3.293mA   -2.932mA   -3.809mA
-601.6mV  -1.347mA   -1.27mA    -1.438mA
0V        0A         0A         0A
10V       0A         0A         0A
[POWER Clamp]
| Voltage   I(typ)   I(min)   I(max)
-5V       445.8uA    298.5uA    885uA
-675.5mV  26.73uA    18.92uA    47.9uA
-623.3mV  22.36uA    15.97uA    39.34uA
-513mV    13.67uA    10.08uA    22.57uA
-460.7mV  9.952uA    7.523uA    15.62uA
-413.3mV  6.934uA    5.41uA     10.2uA
-373.6mV  4.757uA    3.846uA    6.517uA
-316.9mV  2.38uA     2.053uA    2.895uA
-292.1mV  1.646uA    1.465uA    1.905uA
-240mV    673.3nA    634.7nA    719.5nA
0V        0A         0A         0A
10V       0A         0A         0A
[Ramp]
|   typ   min   max
dV/dt_r   1.495V/480.000ps   0.954V/864.000ps   1.911V/352.000ps
dV/dt_f   2.042V/900.000ps   1.606V/1.620ns   2.376V/660.000ps
R_load =  50.000Ohm
|------------------- End of MACH:PLD ------------------------------------------
|------------------- End of Models Section ====================================|
